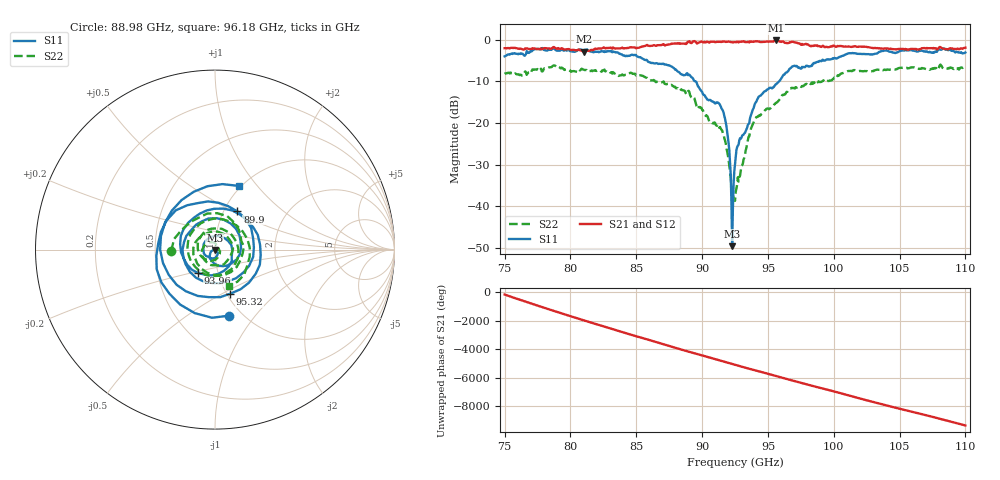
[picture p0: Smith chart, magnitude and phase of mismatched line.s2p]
!Created with skrf (http://scikit-rf.org).
# GHz S RI R 50.0
!freq ReS11 ImS11 ReS21 ImS21 ReS12 ImS12 ReS22 ImS22
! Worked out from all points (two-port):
!   647 points, 75 GHz to 110 GHz, reference 50 ohm
!   highest |S21| = -0.18 dB at 95.59 GHz (marker M1); lowest = -2.9 dB at 81.02 GHz (marker M2)
!   |S21| within 3 dB of the highest: start of sweep to end of sweep
!   lowest |S11| = -49.6 dB at 92.28 GHz (marker M3), VSWR 1.01, Z = 49.9 - j0.318 ohm
!   |S11| at or under -10 dB: 89.49 GHz to 95.85 GHz (6.368 GHz wide, 6.87 % of centre)
!   |S22| runs from -38.7 to -6.0 dB; largest |S21 - S12| = 0.012
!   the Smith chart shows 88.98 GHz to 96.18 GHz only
!   S11 on the Smith chart (normalised r, x): 88.98 GHz: 0.87, -0.75; 89.9 GHz: 1.16, +0.52; 93.96 GHz: 0.80, -0.22; 95.32 GHz: 1.03, -0.55; 96.18 GHz: 0.98, +0.81
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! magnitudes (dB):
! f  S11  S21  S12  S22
! 75 GHz  -4.0  -2.0  -2.1  -8.2
! 80.85 GHz  -2.6  -2.6  -2.6  -7.0
! 81.02 GHz  -2.8  -2.9  -2.9  -7.2
! 86.7 GHz  -5.8  -1.3  -1.3  -10.0
! 88.98 GHz  -8.5  -0.4  -0.4  -12.3
! 89.9 GHz  -12.2  -0.5  -0.5  -16.3
! 91.63 GHz  -17.5  -0.4  -0.4  -22.7
! 91.96 GHz  -23.5  -0.5  -0.5  -27.8
! 92.17 GHz  -32.4  -0.6  -0.6  -33.2
! 92.28 GHz  -49.6  -0.6  -0.6  -36.6
! 92.39 GHz  -34.8  -0.6  -0.6  -38.1
! 92.5 GHz  -30.0  -0.6  -0.6  -38.7
! 92.77 GHz  -25.2  -0.7  -0.6  -34.1
! 93.96 GHz  -15.9  -0.4  -0.4  -19.5
! 95.32 GHz  -11.7  -0.5  -0.5  -16.1
! 95.59 GHz  -10.8  -0.2  -0.2  -15.2
! 96.18 GHz  -8.4  -0.5  -0.5  -13.3
! 96.89 GHz  -6.4  -0.5  -0.5  -11.6
! 98.35 GHz  -6.3  -1.4  -1.4  -10.2
! 101.1 GHz  -3.3  -1.6  -1.6  -7.5
! 104.2 GHz  -2.8  -2.2  -2.2  -7.2
! 110 GHz  -3.1  -1.9  -1.9  -6.5
